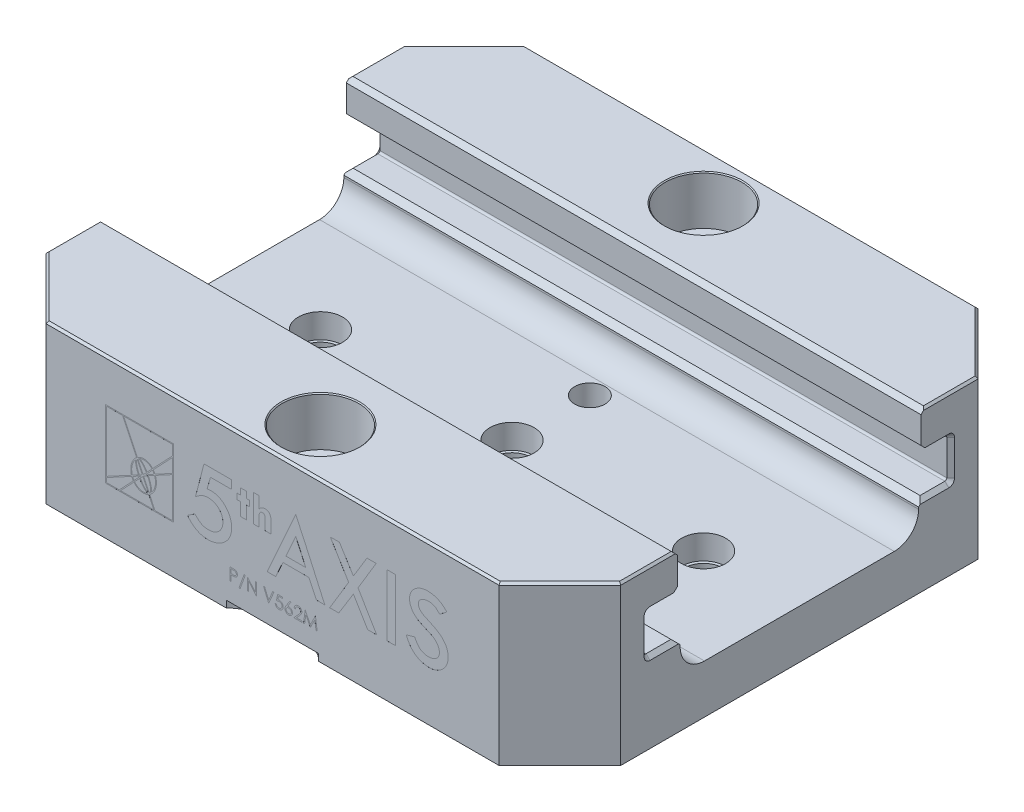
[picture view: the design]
SolidWorks part; units mm, degrees
ref_plane "Front Plane" through (0, 0, 0) normal (0, 0, 1) x (1, 0, 0)
ref_plane "Top Plane" through (0, 0, 0) normal (0, 1, 0) x (1, 0, 0)
ref_plane "Right Plane" through (0, 0, 0) normal (1, 0, 0) x (0, 0, -1)
sketch "Sketch1" plane through (0, 0, 0) normal (0, 1, 0) x (1, 0, 0)
  line L1 (-75, -62.5) -> (75, -62.5)
  line L2 (-75, -62.5) -> (-75, 62.5)
  line L3 (-75, 62.5) -> (75, 62.5)
  line L4 (75, -62.5) -> (75, 62.5)
  line L5 (-75, -62.5) -> (75, 62.5) construction
  line L6 (-75, 62.5) -> (75, -62.5) construction
  circle A0 centre (0, 0) radius 88.9 construction
  circle A1 centre (0, 0) radius 63.5 construction
  point P0 (0, 0)
  dimension "D3" = 127
  dimension "D4" = 177.8
  dimension "D1" = 150
  dimension "D2" = 125
extrude "Boss-Extrude1" add sketch "Sketch1" along normal blind 41.275
sketch "Sketch4" plane through (0, 0, 0) normal (1, 0, 0) x (0, 0, -1)
  line L0 (-31.75, 41.275) -> (31.75, 41.275)
  line L1 (-62.5, 41.275) -> (62.5, 41.275) construction
  line L2 (31.115, 12.7) -> (31.115, 20.955)
  line L3 (31.115, 20.955) -> (39.497, 20.955)
  line L4 (39.497, 20.955) -> (39.497, 31.115)
  line L5 (39.497, 31.115) -> (31.75, 31.115)
  line L6 (31.75, 31.115) -> (31.75, 41.275)
  line L7 (-31.115, 12.7) -> (-31.115, 20.955)
  line L8 (-31.115, 20.955) -> (-39.497, 20.955)
  line L9 (-39.497, 20.955) -> (-39.497, 31.115)
  line L10 (-39.497, 31.115) -> (-31.75, 31.115)
  line L11 (-31.75, 31.115) -> (-31.75, 41.275)
  line L12 (-62.5, 0) -> (62.5, 0) construction
  line L14 (-31.115, 12.7) -> (31.115, 12.7)
  line L17 (0, 0) -> (0, 41.275) construction
  point P6 (0, 12.7)
  point P14 (0, 41.275)
  dimension "D1" = 78.994
  dimension "D2" = 63.5
  dimension "D3" = 10.16
  dimension "D4" = 8.255
  dimension "D5" = 12.7
  dimension "D6" = 62.23
  dimension "D7" = 8.636
extrude "Cut-Extrude2 INTERIOR CUT" cut sketch "Sketch4" against normal through all and the other way through all
hole_wizard "CBORE for M12 SHCS1" positions "Sketch11" profile "Sketch10" counterbore size "M12" standard "ANSI Metric"
sketch "Sketch11" plane through (0, 41.275, 0) normal (0, 1, 0) x (-1, 0, 0)
  line L0 (0, 50) -> (0, -50) construction
  point P0 (0, -50)
  point P1 (0, 50)
  dimension "D1" = 100
sketch "Sketch10" plane through (0, 41.275, -50) normal (1, 0, 0) x (0, 0, 1)
  line L0 (0, 0) -> (0, 41.275)
  line L1 (0, 41.275) -> (6.5, 41.275)
  line L3 (6.5, 41.275) -> (6.5, 12.762)
  line L4 (10, 12.762) -> (6.5, 12.762)
  line L5 (10, 12.762) -> (10, 0.25)
  line L6 (10, 0.25) -> (10.25, 0)
  line L7 (10.25, 0) -> (0, 0)
  line L8 (-10, 0.25) -> (-10.25, 0) construction
  line L11 (0, -6.35) -> (0, 107.95) construction
  dimension "Thru Hole Dia." = 13
  dimension "Thru Hole Depth" = 41.275
  dimension "C'Bore Dia." = 20
  dimension "C'Bore Depth" = 12.762
  dimension "Near C'Sink Dia." = 20.5
  dimension "Near C'Sink Angle" = 90
fillet "Fillet1" radius 6.35 2 edges at (0, 12.7, -31.115) (0, 12.7, 31.115)
sketch "Sketch6" plane through (0, 0, 0) normal (0, -1, 0) x (1, 0, 0)
  line L0 (-75, 0) -> (75, 0) construction
  line L1 (-75, -62.5) -> (-75, 62.5) construction
  line L2 (75, 62.5) -> (75, -62.5) construction
  circle A0 centre (0, -10.16) radius 3.175
  circle A1 centre (0, 10.16) radius 3.175
  dimension "D1" = 6.35
  dimension "D2" = 10.16
  dimension "D3" = 11.5
extrude "Cut-Extrude4 CENTER BLOCK DP" [suppressed] cut sketch "Sketch6" against normal through all
hole_wizard "CBORE for 5/16 Socket Head Cap Screw1" positions "Sketch8" profile "Sketch7" counterbore size "5/16" standard "ANSI Inch"
sketch "Sketch8" plane through (0, 0, 0) normal (0, -1, 0) x (1, 0, 0)
  line L0 (0, -20.32) -> (0, 20.32) construction
  point P0 (0, -20.32)
  point P6 (0, 20.32)
  dimension "D1" = 40.64
sketch "Sketch7" plane through (0, 0, -20.32) normal (1, 0, 0) x (0, 0, -1)
  line L0 (0, 0) -> (0, 41.275)
  line L1 (0, 41.275) -> (3.9687, 41.275)
  line L3 (3.9687, 41.275) -> (3.9688, 6.096)
  line L4 (3.9688, 6.096) -> (6.7475, 6.096)
  line L5 (6.7475, 6.096) -> (6.7475, 0)
  line L7 (6.7475, 0) -> (0, 0)
  line L11 (0, -6.35) -> (0, 107.95) construction
  dimension "Thru Hole Dia." = 7.9375
  dimension "Thru Hole Depth" = 41.275
  dimension "C'Bore Dia." = 13.495
  dimension "C'Bore Depth" = 6.096
sketch "Sketch12" plane through (0, 0, -62.5) normal (0, 0, -1) x (-1, 0, 0)
  line L0 (16.764, 11.684) -> (42.164, 11.684) construction
  line L1 (16.764, 15.748) -> (42.164, 15.748)
  line L2 (16.764, 7.62) -> (42.164, 7.62)
  line L4 (0, 0) -> (0, 41.275) construction
  line L5 (-75, 41.275) -> (75, 41.275) construction
  line L6 (-16.764, 11.684) -> (-42.164, 11.684) construction
  line L7 (-16.764, 15.748) -> (-42.164, 15.748)
  line L8 (-16.764, 7.62) -> (-42.164, 7.62)
  line L11 (-75, 0) -> (75, 0) construction
  arc A0 (16.764, 15.748) -> (16.764, 7.62) centre (16.764, 11.684) ccw
  arc A1 (42.164, 7.62) -> (42.164, 15.748) centre (42.164, 11.684) ccw
  arc A2 (-16.764, 15.748) -> (-16.764, 7.62) centre (-16.764, 11.684) cw
  arc A3 (-42.164, 7.62) -> (-42.164, 15.748) centre (-42.164, 11.684) cw
  point P2 (29.464, 11.684)
  point P16 (-29.464, 11.684)
  dimension "D1" = 8.128
  dimension "D2" = 25.4
  dimension "D3" = 12.7
  dimension "D4" = 7.62
  dimension "D5" = 14.9262
extrude "Cut-Extrude6 CHIP CHANNELS" [suppressed] cut sketch "Sketch12" against normal blind 39.37
sketch "Sketch2" [suppressed] plane through (0, 12.7, 0) normal (0, 1, 0) x (1, 0, 0)
  line L1 (20.449, 23.495) -> (38.479, 23.495) construction
  line L2 (20.449, 31.115) -> (38.479, 31.115)
  line L3 (20.449, 15.875) -> (38.479, 15.875)
  line L5 (0, -62.5) -> (0, 62.5) construction
  line L6 (-75, -62.5) -> (75, -62.5) construction
  line L7 (75, 62.5) -> (-75, 62.5) construction
  line L8 (-75, 0) -> (75, 0) construction
  line L9 (-75, -24.765) -> (-75, 24.765) construction
  line L10 (75, -24.765) -> (75, 24.765) construction
  line L11 (-75, 31.115) -> (75, 31.115) construction
  line L12 (12.829, 23.13) -> (12.829, 24.765) construction
  line L13 (46.099, 24.765) -> (46.099, 23.13) construction
  line L14 (-20.449, 23.495) -> (-38.479, 23.495) construction
  line L15 (-20.449, 31.115) -> (-38.479, 31.115)
  line L16 (-20.449, 15.875) -> (-38.479, 15.875)
  line L17 (-20.449, -23.495) -> (-38.479, -23.495) construction
  line L18 (-20.449, -31.115) -> (-38.479, -31.115)
  line L19 (-20.449, -15.875) -> (-38.479, -15.875)
  line L20 (20.449, -23.495) -> (38.479, -23.495) construction
  line L21 (20.449, -31.115) -> (38.479, -31.115)
  line L22 (20.449, -15.875) -> (38.479, -15.875)
  arc A0 (20.449, 31.115) -> (20.449, 15.875) centre (20.449, 23.495) ccw
  arc A1 (38.479, 15.875) -> (38.479, 31.115) centre (38.479, 23.495) ccw
  arc A2 (-20.449, 31.115) -> (-20.449, 15.875) centre (-20.449, 23.495) cw
  arc A3 (-38.479, 15.875) -> (-38.479, 31.115) centre (-38.479, 23.495) cw
  arc A4 (-20.449, -31.115) -> (-20.449, -15.875) centre (-20.449, -23.495) ccw
  arc A5 (-38.479, -15.875) -> (-38.479, -31.115) centre (-38.479, -23.495) ccw
  arc A6 (20.449, -31.115) -> (20.449, -15.875) centre (20.449, -23.495) cw
  arc A7 (38.479, -15.875) -> (38.479, -31.115) centre (38.479, -23.495) cw
  point P2 (29.464, 23.495)
  point P29 (-29.464, 23.495)
  point P36 (-29.464, -23.495)
  point P43 (29.464, -23.495)
  dimension "D3" = 12.7
  dimension "D2" = 40.64
  dimension "D1" = 15.24
extrude "Cut-Extrude1 CHIP CHANNEL END" [suppressed] cut sketch "Sketch2" against normal blind 5.08 and the other way through all
mirror "Mirror1" [suppressed] about plane through (0, 0, 0) normal (0, 0, 1)
chamfer "Chamfer1" distance 15.875 angle 45 4 edges at (-75, 20.6375, -62.5) (-75, 20.6375, 62.5) (75, 20.6375, -62.5) (75, 20.6375, 62.5)
sketch "Sketch13" plane through (0, 0, 0) normal (0, -1, 0) x (1, 0, 0)
  circle A0 centre (0, 0) radius 5.0064
  dimension "D1" = 10.0127
extrude "Cut-Extrude7 CENTER LOCATING BORE" cut sketch "Sketch13" against normal blind 7.62
sketch "Sketch16" plane through (0, 0, 0) normal (0, -1, 0) x (1, 0, 0)
  line L0 (0, -62.5) -> (0, 62.5) construction
  line L1 (59.125, -62.5) -> (-59.125, -62.5) construction
  line L2 (-59.125, 62.5) -> (59.125, 62.5) construction
  circle A0 centre (-50, 0) radius 5.0063
  circle A1 centre (50, 0) radius 5.0063
  dimension "D1" = 10.0127
  dimension "D3" = 50
  dimension "D2" = 50
extrude "Cut-Extrude8 CLOCKING BORE" cut sketch "Sketch16" against normal blind 7.62
sketch "Sketch32" plane through (0, 0, 0) normal (0, -1, 0) x (1, 0, 0)
  point P0 (50, 0)
  point P1 (0, 0)
  point P3 (-50, 0)
hole_wizard "1/2-20 Tapped Hole2" positions "Sketch34" profile "Sketch33" tap size "1/2-20" standard "ANSI Inch"
sketch "Sketch34" plane through (0, 12.7, 0) normal (0, 1, 0) x (1, 0, 0)
  point P0 (50, 0)
  point P2 (0, 0)
  point P4 (-50, 0)
sketch "Sketch33" plane through (50, 12.7, 0) normal (1, 0, 0) x (0, 0, 1)
  line L0 (0, 0) -> (0, 6.35)
  line L1 (0, 6.35) -> (5.7544, 6.35)
  line L2 (5.7544, 6.35) -> (5.7544, 0)
  line L5 (5.7544, 0) -> (0, 0)
  line L10 (0, 6.35) -> (-5.7544, 6.35) construction
  line L11 (0, -6.35) -> (0, 107.95) construction
  dimension "Tap Drill Dia." = 11.5087
  dimension "Tap Drill Depth" = 6.35
  dimension "Drill Angle" = 180
hole_wizard "M6x1.0 Tapped Hole1" positions "Sketch15" profile "Sketch14" tap size "M6x1.0" standard "ANSI Metric"
sketch "Sketch15" plane through (0, 5.969, 0) normal (0, -1, 0) x (1, 0, 0)
  point P0 (0, 0)
  point P4 (-50, 0)
  point P7 (50, 0)
sketch "Sketch14" plane through (0, 5.969, 0) normal (1, 0, 0) x (0, 0, -1)
  line L0 (0, 0) -> (0, 35.306)
  line L1 (0, 35.306) -> (2.5, 35.306)
  line L2 (2.5, 35.306) -> (2.5, 0)
  line L5 (2.5, 0) -> (0, 0)
  line L11 (0, -6.35) -> (0, 107.95) construction
  dimension "Thru Tap Drill Dia." = 5
  dimension "Thru Tap Drill Depth" = 35.306
chamfer "Chamfer3" distance 1.397 angle 45 2 edges at (0, 20.955, 31.115) (0, 20.955, -31.115)
fillet "Fillet3" radius 0.508 4 edges at (0, 20.955, -39.497) (0, 31.115, -39.497) (0, 20.955, 39.497) (0, 31.115, 39.497)
chamfer "Chamfer4" distance 0.5334 angle 45 12 edges at (75, 41.275, 39.1875) (67.0625, 41.275, 54.5625) (0, 41.275, 62.5) (-67.0625, 41.275, 54.5625) (-75, 41.275, 39.1875) (75, 41.275, -39.1875) (67.0625, 41.275, -54.5625) (0, 41.275, -62.5) (-67.0625, 41.275, -54.5625) (-75, 41.275, -39.1875) (0, 41.275, 31.75) (0, 41.275, -31.75)
sketch "Sketch20" plane through (0, 0, 0) normal (0, -1, 0) x (1, 0, 0)
  line L0 (-75, 0) -> (75, 0) construction
  line L1 (-75, -46.625) -> (-75, 46.625) construction
  line L2 (75, 46.625) -> (75, -46.625) construction
  line L3 (-6.35, 67.58) -> (6.35, 67.58) construction
  line L4 (-6.35, 75.2) -> (6.35, 75.2)
  line L5 (-6.35, 59.96) -> (6.35, 59.96)
  line L6 (-59.125, 62.5) -> (59.125, 62.5) construction
  line L7 (-6.35, -67.58) -> (6.35, -67.58) construction
  line L8 (-6.35, -75.2) -> (6.35, -75.2)
  line L9 (-6.35, -59.96) -> (6.35, -59.96)
  arc A0 (-6.35, 75.2) -> (-6.35, 59.96) centre (-6.35, 67.58) ccw
  arc A1 (6.35, 59.96) -> (6.35, 75.2) centre (6.35, 67.58) ccw
  arc A2 (-6.35, -75.2) -> (-6.35, -59.96) centre (-6.35, -67.58) cw
  arc A3 (6.35, -59.96) -> (6.35, -75.2) centre (6.35, -67.58) cw
  point P8 (0, 67.58)
  point P18 (0, -67.58)
  dimension "D3" = 7.62
  dimension "D1" = 2.54
  dimension "D2" = 12.7
extrude "Cut-Extrude9 PRY SLOTS" cut sketch "Sketch20" against normal blind 1.778
sketch "Sketch26" plane through (0, 0, 0) normal (0, -1, 0) x (1, 0, 0)
  line L8 (-75, 46.625) -> (-75, -46.625)
  line L9 (-75, -46.625) -> (-59.125, -62.5)
  line L10 (-59.125, -62.5) -> (-12.0296, -62.5)
  line L11 (59.125, -62.5) -> (75, -46.625)
  line L12 (75, -46.625) -> (75, 46.625)
  line L13 (75, 46.625) -> (59.125, 62.5)
  line L14 (59.125, 62.5) -> (12.0296, 62.5)
  line L15 (-59.125, 62.5) -> (-75, 46.625)
  line L16 (-75, 46.625) -> (-75, -46.625)
  line L17 (-75, -46.625) -> (-59.125, -62.5)
  line L18 (-59.125, -62.5) -> (-12.0296, -62.5)
  line L19 (59.125, -62.5) -> (75, -46.625)
  line L20 (75, -46.625) -> (75, 46.625)
  line L21 (75, 46.625) -> (59.125, 62.5)
  line L22 (59.125, 62.5) -> (12.0296, 62.5)
  line L23 (-59.125, 62.5) -> (-75, 46.625)
  line L28 (-6.35, -59.96) -> (6.35, -59.96)
  line L29 (-6.35, -59.96) -> (6.35, -59.96)
  line L30 (12.0296, -62.5) -> (59.125, -62.5)
  line L31 (12.0296, -62.5) -> (59.125, -62.5)
  line L32 (6.35, 59.96) -> (-6.35, 59.96)
  line L33 (6.35, 59.96) -> (-6.35, 59.96)
  line L34 (-12.0296, 62.5) -> (-59.125, 62.5)
  line L35 (-12.0296, 62.5) -> (-59.125, 62.5)
  circle A0 centre (0, -50) radius 6.5 construction
  circle A1 centre (0, 50) radius 6.5 construction
  circle A2 centre (0, 50) radius 6.5
  circle A3 centre (0, -50) radius 6.5
  arc A8 (-6.35, -59.96) -> (-12.0296, -62.5) centre (-6.35, -67.58) ccw
  arc A9 (-6.35, -59.96) -> (-12.0296, -62.5) centre (-6.35, -67.58) ccw
  arc A10 (12.0296, -62.5) -> (6.35, -59.96) centre (6.35, -67.58) ccw
  arc A11 (12.0296, -62.5) -> (6.35, -59.96) centre (6.35, -67.58) ccw
  arc A12 (6.35, 59.96) -> (12.0296, 62.5) centre (6.35, 67.58) ccw
  arc A13 (6.35, 59.96) -> (12.0296, 62.5) centre (6.35, 67.58) ccw
  arc A14 (-12.0296, 62.5) -> (-6.35, 59.96) centre (-6.35, 67.58) ccw
  arc A15 (-12.0296, 62.5) -> (-6.35, 59.96) centre (-6.35, 67.58) ccw
  dimension "D1" = 0
extrude "Boss-Extrude5 MILL OP2 " [suppressed] add sketch "Sketch26" along normal blind 1.016
sketch "Sketch23" [suppressed] plane through (0, 0, 0) normal (0, -1, 0) x (1, 0, 0)
  line L8 (-75, 46.625) -> (-75, -46.625)
  line L9 (-75, -46.625) -> (-59.125, -62.5)
  line L10 (-59.125, -62.5) -> (-12.0296, -62.5)
  line L11 (59.125, -62.5) -> (75, -46.625)
  line L12 (75, -46.625) -> (75, 46.625)
  line L13 (75, 46.625) -> (59.125, 62.5)
  line L14 (59.125, 62.5) -> (12.0296, 62.5)
  line L15 (-59.125, 62.5) -> (-75, 46.625)
  line L16 (-75, 46.625) -> (-75, -46.625)
  line L17 (-75, -46.625) -> (-59.125, -62.5)
  line L18 (-59.125, -62.5) -> (-12.0296, -62.5)
  line L19 (59.125, -62.5) -> (75, -46.625)
  line L20 (75, -46.625) -> (75, 46.625)
  line L21 (75, 46.625) -> (59.125, 62.5)
  line L22 (59.125, 62.5) -> (12.0296, 62.5)
  line L23 (-59.125, 62.5) -> (-75, 46.625)
  line L28 (-6.35, -59.96) -> (6.35, -59.96)
  line L29 (-6.35, -59.96) -> (6.35, -59.96)
  line L30 (12.0296, -62.5) -> (59.125, -62.5)
  line L31 (12.0296, -62.5) -> (59.125, -62.5)
  line L32 (6.35, 59.96) -> (-6.35, 59.96)
  line L33 (6.35, 59.96) -> (-6.35, 59.96)
  line L34 (-12.0296, 62.5) -> (-59.125, 62.5)
  line L35 (-12.0296, 62.5) -> (-59.125, 62.5)
  circle A0 centre (-50, 0) radius 5.0063 construction
  circle A1 centre (0, 50) radius 6.5 construction
  circle A2 centre (0, 20.32) radius 6.7475 construction
  circle A3 centre (0, 0) radius 5.0064 construction
  circle A4 centre (0, -20.32) radius 6.7475 construction
  circle A5 centre (0, -50) radius 6.5 construction
  circle A6 centre (-50, 0) radius 5.0063
  circle A7 centre (0, 50) radius 6.5
  circle A8 centre (0, 20.32) radius 6.7475
  circle A9 centre (0, 0) radius 5.0064
  circle A10 centre (0, -20.32) radius 6.7475
  circle A11 centre (0, -50) radius 6.5
  circle A12 centre (50, 0) radius 5.0063
  arc A16 (-6.35, -59.96) -> (-12.0296, -62.5) centre (-6.35, -67.58) ccw
  arc A17 (-6.35, -59.96) -> (-12.0296, -62.5) centre (-6.35, -67.58) ccw
  arc A18 (12.0296, -62.5) -> (6.35, -59.96) centre (6.35, -67.58) ccw
  arc A19 (12.0296, -62.5) -> (6.35, -59.96) centre (6.35, -67.58) ccw
  arc A20 (6.35, 59.96) -> (12.0296, 62.5) centre (6.35, 67.58) ccw
  arc A21 (6.35, 59.96) -> (12.0296, 62.5) centre (6.35, 67.58) ccw
  arc A22 (-12.0296, 62.5) -> (-6.35, 59.96) centre (-6.35, 67.58) ccw
  arc A23 (-12.0296, 62.5) -> (-6.35, 59.96) centre (-6.35, 67.58) ccw
  dimension "D1" = 0
extrude "Boss-Extrude4 MILL OP3" [suppressed] add sketch "Sketch23" along normal blind 0.254
sketch "Sketch27" [suppressed] plane through (0, 0, 0) normal (1, 0, 0) x (0, 0, -1)
  line L0 (63.5, -1.016) -> (-63.5, -1.016)
  line L1 (46.99, -1.016) -> (-46.99, -1.016) construction
  line L2 (-63.5, -1.016) -> (-63.5, -3.048)
  line L3 (-63.5, -3.048) -> (-12.7, -3.048)
  line L4 (-12.7, -3.048) -> (-16.256, -6.604)
  line L5 (-16.256, -6.604) -> (-16.256, -6.858)
  line L6 (-16.256, -6.858) -> (16.256, -6.858)
  line L7 (0, -6.858) -> (0, -1.016) construction
  line L8 (16.256, -6.604) -> (16.256, -6.858)
  line L9 (12.7, -3.048) -> (16.256, -6.604)
  line L10 (63.5, -3.048) -> (12.7, -3.048)
  line L11 (63.5, -1.016) -> (63.5, -3.048)
  dimension "D1" = 45
  dimension "D2" = 0.254
  dimension "D3" = 25.4
  dimension "D4" = 3.81
  dimension "D5" = 127
  dimension "D6" = 3.048
extrude "Boss-Extrude6 MILL OP2 DOVETAIL" [suppressed] add sketch "Sketch27" along normal mid plane 154.94
hole_wizard "Ø7.7 (7.7) Diameter Hole1" positions "Sketch25" profile "Sketch24" hole size "Ø7.7" standard "ANSI Metric"
sketch "Sketch25" plane through (0, 12.7, 0) normal (0, 1, 0) x (-1, 0, 0)
  point P0 (0, -20.32)
  point P3 (0, 20.32)
sketch "Sketch24" plane through (0, 12.7, -20.32) normal (1, 0, 0) x (0, 0, 1)
  line L0 (0, 0) -> (0, 11.1945)
  line L1 (0, 11.1945) -> (3.8354, 8.89)
  line L2 (3.8354, 8.89) -> (3.8354, 0)
  line L5 (3.8354, 0) -> (0, 0)
  line L10 (0, 11.1945) -> (-3.8354, 8.89) construction
  line L11 (0, -6.35) -> (0, 107.95) construction
  dimension "Hole Dia." = 7.6225
  dimension "Hole Depth" = 8.89
  dimension "Drill Angle" = 118
chamfer "Chamfer5" distance 2.032 angle 45 2 edges at (0, 31.115, -31.75) (0, 31.115, 31.75)
chamfer "Chamfer6" distance 1.1684 angle 45 2 edges at (0, 41.275, -31.75) (0, 41.275, 31.75)
sketch "Sketch28" plane through (0, 41.275, 0) normal (0, 1, 0) x (1, 0, 0)
  line L6 (-74.4666, 46.4041) -> (-74.4666, 32.9184)
  line L7 (-74.4666, 32.9184) -> (74.4666, 32.9184)
  line L8 (74.4666, 32.9184) -> (74.4666, 46.4041)
  line L9 (74.4666, 46.4041) -> (58.9041, 61.9666)
  line L10 (58.9041, 61.9666) -> (-58.9041, 61.9666)
  line L11 (-58.9041, 61.9666) -> (-74.4666, 46.4041)
  line L12 (-74.4666, 46.4041) -> (-74.4666, 32.9184)
  line L13 (-74.4666, 32.9184) -> (74.4666, 32.9184)
  line L14 (74.4666, 32.9184) -> (74.4666, 46.4041)
  line L15 (74.4666, 46.4041) -> (58.9041, 61.9666)
  line L16 (58.9041, 61.9666) -> (-58.9041, 61.9666)
  line L17 (-58.9041, 61.9666) -> (-74.4666, 46.4041)
  line L18 (74.4666, -46.4041) -> (74.4666, -32.9184)
  line L19 (74.4666, -32.9184) -> (-74.4666, -32.9184)
  line L20 (-74.4666, -32.9184) -> (-74.4666, -46.4041)
  line L21 (-74.4666, -46.4041) -> (-58.9041, -61.9666)
  line L22 (-58.9041, -61.9666) -> (58.9041, -61.9666)
  line L23 (58.9041, -61.9666) -> (74.4666, -46.4041)
  line L24 (74.4666, -46.4041) -> (74.4666, -32.9184)
  line L25 (74.4666, -32.9184) -> (-74.4666, -32.9184)
  line L26 (-74.4666, -32.9184) -> (-74.4666, -46.4041)
  line L27 (-74.4666, -46.4041) -> (-58.9041, -61.9666)
  line L28 (-58.9041, -61.9666) -> (58.9041, -61.9666)
  line L29 (58.9041, -61.9666) -> (74.4666, -46.4041)
  circle A0 centre (0, -50) radius 10.25 construction
  circle A1 centre (0, -50) radius 10.25
  circle A2 centre (0, 50) radius 10.25 construction
  circle A3 centre (0, 50) radius 10.25
  dimension "D1" = 0
  dimension "D2" = 0
extrude "Boss-Extrude2 TOP SURFACE MILL OP2 AND 3 1" [suppressed] add sketch "Sketch28" along normal blind 0.2286 draft 45
chamfer "Chamfer7" distance 1.016 angle 45 20 edges at (75, 20.955, -35.7505) (75, 31.115, -36.3855) (75, 21.1038, -39.3482) (75, 30.9662, -39.3482) (75, 26.035, -39.497) (-75, 20.955, -35.7505) (-75, 31.115, -36.3855) (-75, 21.1038, -39.3482) (-75, 30.9662, -39.3482) (-75, 26.035, -39.497) (-75, 31.115, 36.3855) (-75, 20.955, 35.7505) (-75, 30.9662, 39.3482) (-75, 21.1038, 39.3482) (-75, 26.035, 39.497) (75, 31.115, 36.3855) (75, 20.955, 35.7505) (75, 30.9662, 39.3482) (75, 21.1038, 39.3482) (75, 26.035, 39.497)
ref_plane "Plane1" [suppressed] through (0, 20.6375, 0) normal (0, 1, 0) x (1, 0, 0)
sketch "Sketch29" plane through (75, 0, 0) normal (1, 0, 0) x (0, 0, -1)
  line L0 (0, 0) -> (0, 1.6452)
  line L1 (-46.625, 0) -> (46.625, 0) construction
  line L2 (0, 1.6452) -> (0, 0)
  line L3 (0, -1.358) -> (0, 0)
  circle A0 centre (0, 0) radius 0.9256
ref_plane "Plane2" through (75, 40.1066, 31.75) normal (0, -1, 0) x (-1, 0, 0)
sketch "Sketch37" plane through (0, 0, -62.5) normal (0, 0, -1) x (-1, 0, 0)
  line L78 (31.5818, 30.329) -> (29.4648, 30.329)
  line L79 (31.5818, 14.2731) -> (31.5818, 30.329)
  line L80 (29.4315, 30.2317) -> (29.4315, 14.2731)
  line L81 (26.5655, 30.329) -> (24.1555, 30.329)
  line L82 (24.3187, 14.2396) -> (26.6959, 14.2396)
  line L83 (9.0103, 18.3759) -> (10.9316, 14.2731)
  line L84 (2.2364, 18.3759) -> (9.0103, 18.3759)
  line L85 (3.0182, 20.2002) -> (8.1643, 20.2002)
  line L86 (-3.9993, 23.2302) -> (-3.9993, 26.0708)
  line L87 (-5.5171, 23.2302) -> (-3.9993, 23.2302)
  line L88 (-5.5171, 30.3625) -> (-5.5171, 23.2302)
  line L89 (-3.9993, 30.3625) -> (-5.5171, 30.3625)
  line L90 (-3.9993, 27.2737) -> (-3.9993, 30.3625)
  line L91 (-0.8833, 23.2302) -> (-0.8833, 25.9583)
  line L92 (-2.4011, 23.2302) -> (-0.8833, 23.2302)
  line L93 (-2.4011, 26.2774) -> (-2.4011, 23.2302)
  line L94 (-7.3448, 26.5811) -> (-6.4844, 26.5811)
  line L95 (-7.3448, 23.2302) -> (-7.3448, 26.5811)
  line L96 (-8.8626, 23.2302) -> (-7.3448, 23.2302)
  line L97 (-8.8626, 26.5811) -> (-8.8626, 23.2302)
  line L98 (-9.723, 26.5811) -> (-8.8626, 26.5811)
  line L99 (-9.723, 28.0643) -> (-9.723, 26.5811)
  line L100 (-8.8626, 28.0643) -> (-9.723, 28.0643)
  line L101 (-8.8626, 29.7121) -> (-8.8626, 28.0643)
  line L102 (-7.3448, 29.7121) -> (-8.8626, 29.7121)
  line L103 (-7.3448, 28.0643) -> (-7.3448, 29.7121)
  line L104 (-6.4844, 28.0643) -> (-7.3448, 28.0643)
  line L105 (-6.4844, 26.5811) -> (-6.4844, 28.0643)
  line L106 (-26.3243, 30.9152) -> (-44.0736, 30.9152)
  line L107 (-26.3243, 13.166) -> (-26.3243, 30.9152)
  line L108 (-44.0736, 13.166) -> (-26.3243, 13.166)
  line L109 (-44.0736, 30.9152) -> (-44.0736, 13.166)
  line L110 (-36.6713, 17.0962) -> (-40.1689, 13.4149)
  line L111 (-40.1689, 13.4149) -> (-31.4507, 13.4149)
  line L112 (-31.4507, 13.4149) -> (-32.7806, 16.2246)
  line L113 (-39.6164, 30.6663) -> (-43.8247, 30.6663)
  line L114 (-43.8247, 30.6663) -> (-43.8247, 14.8252)
  line L115 (-43.8247, 14.8252) -> (-37.3034, 18.3357)
  line L116 (-37.0835, 18.4541) -> (-35.5011, 19.306)
  line L117 (-35.6596, 22.8889) -> (-34.2801, 19.9744)
  line L118 (-34.2801, 19.9744) -> (-33.4239, 20.8756)
  line L119 (-37.2217, 18.097) -> (-43.8247, 14.5425)
  line L120 (-43.8247, 14.5425) -> (-43.8247, 13.4149)
  line L121 (-43.8247, 13.4149) -> (-40.5123, 13.4149)
  line L122 (-40.5123, 13.4149) -> (-36.8187, 17.3025)
  line L123 (-36.6428, 17.4876) -> (-35.3027, 18.8981)
  line L124 (-35.3942, 19.0808) -> (-37.0037, 18.2144)
  line L125 (-26.5733, 23.8295) -> (-31.0756, 21.4057)
  line L126 (-32.5661, 16.3533) -> (-31.1753, 13.4149)
  line L127 (-31.1753, 13.4149) -> (-26.5733, 13.4149)
  line L128 (-26.5733, 13.4149) -> (-26.5733, 23.8295)
  line L129 (-26.5733, 30.6663) -> (-39.341, 30.6663)
  line L130 (-31.7859, 22.5996) -> (-26.5733, 28.086)
  line L131 (-26.5733, 28.086) -> (-26.5733, 30.6663)
  line L132 (-26.5733, 24.1122) -> (-26.5733, 27.7246)
  line L133 (-26.5733, 27.7246) -> (-31.626, 22.4065)
  line L134 (-31.1705, 21.6373) -> (-26.5733, 24.1122)
  line L135 (-33.245, 21.0639) -> (-31.9582, 22.4182)
  line L136 (-35.2815, 19.4242) -> (-34.4954, 19.8474)
  line L137 (-34.4954, 19.8474) -> (-35.8493, 22.7078)
  line L138 (-35.1799, 18.666) -> (-36.4975, 17.2792)
  line L139 (-35.1207, 19.0896) -> (-34.8515, 19.373)
  line L140 (-34.8515, 19.373) -> (-35.1749, 19.1989)
  line L141 (-32.9527, 16.5882) -> (-34.3498, 19.5397)
  line L142 (-34.3498, 19.5397) -> (-34.9995, 18.8558)
  line L143 (-34.1693, 19.7403) -> (-32.681, 16.5961)
  line L144 (-33.1224, 20.3038) -> (-34.1693, 19.7403)
  line L145 (-33.2978, 20.6469) -> (-33.5989, 20.33)
  line L146 (-33.5989, 20.33) -> (-33.2343, 20.5263)
  line L147 (-33.0151, 20.6443) -> (-31.3878, 21.5203)
  line L148 (-31.7998, 22.2236) -> (-33.1174, 20.8367)
  line L149 (-31.2936, 21.2884) -> (-32.9031, 20.4219)
  line L150 (-11.1498, 30.3625) -> (-18.3478, 30.3625)
  line L151 (-11.1498, 28.1793) -> (-11.1498, 30.3625)
  line L152 (-16.6869, 28.1793) -> (-11.1498, 28.1793)
  line L153 (-39.341, 30.6663) -> (-35.7706, 23.1234)
  line L154 (-35.9755, 22.9744) -> (-39.6164, 30.6663)
  ellipse E12 centre (-34.1486, 19.7514) end of major axis (-33.8382, 23.4014) minor radius 3.1023 (-37.0835, 18.4541) -> (-36.2067, 22.4233) cw
  ellipse E13 centre (-34.1486, 19.7514) end of major axis (-35.6596, 22.8889) minor radius 1.1644 (-35.6596, 22.8889) -> (-33.4239, 20.8756) cw
  ellipse E14 centre (-34.1486, 19.7514) end of major axis (-33.8382, 23.4014) minor radius 3.1023 (-36.6428, 17.4876) -> (-37.0037, 18.2144) cw
  ellipse E15 centre (-34.1486, 19.7514) end of major axis (-35.6596, 22.8889) minor radius 1.1644 (-35.2815, 19.4242) -> (-35.8493, 22.7078) cw
  ellipse E16 centre (-34.1486, 19.7514) end of major axis (-33.8382, 23.4014) minor radius 3.1023 (-33.0648, 16.3592) -> (-36.4975, 17.2792) cw
  ellipse E17 centre (-34.1486, 19.7514) end of major axis (-35.6596, 22.8889) minor radius 1.1644 (-35.1207, 19.0896) -> (-35.1749, 19.1989) cw
  ellipse E18 centre (-34.1486, 19.7514) end of major axis (-35.6596, 22.8889) minor radius 1.1644 (-32.9527, 16.5882) -> (-34.9995, 18.8558) cw
  ellipse E19 centre (-34.1486, 19.7514) end of major axis (-35.6596, 22.8889) minor radius 1.1644 (-33.1224, 20.3038) -> (-32.681, 16.5961) cw
  ellipse E20 centre (-34.1486, 19.7514) end of major axis (-35.6596, 22.8889) minor radius 1.1644 (-33.2978, 20.6469) -> (-33.2343, 20.5263) cw
  ellipse E21 centre (-34.1486, 19.7514) end of major axis (-33.8382, 23.4014) minor radius 3.1023 (-31.7998, 22.2236) -> (-31.3878, 21.5203) cw
  ellipse E22 centre (-34.1486, 19.7514) end of major axis (-33.8382, 23.4014) minor radius 3.1023 (-31.2936, 21.2884) -> (-32.0906, 17.0795) cw
  ellipse E23 centre (-34.1486, 19.7514) end of major axis (-33.8382, 23.4014) minor radius 3.1023 (-35.2325, 23.1436) -> (-31.9582, 22.4182) cw
  spline S66 degree 3 poles (41.5797, 28.3758) (42.307, 28.091) (42.6361, 27.5026) (43.1754, 27.1378) knots 0 0 0 0 1 1 1 1
  spline S67 degree 3 poles (37.6711, 27.3004) (38.1086, 28.3917) (40.1449, 28.9369) (41.5797, 28.3758) knots 1 1 1 1 2 2 2 2
  spline S68 degree 3 poles (37.7039, 25.9974) (37.4988, 26.4504) (37.5141, 26.9082) (37.6711, 27.3004) knots 2 2 2 2 3 3 3 3
  spline S69 degree 3 poles (40.6675, 24.0115) (39.5316, 24.5206) (38.1385, 25.0374) (37.7039, 25.9974) knots 3 3 3 3 4 4 4 4
  spline S70 degree 3 poles (45.3252, 18.7995) (45.161, 21.6844) (42.868, 23.0236) (40.6675, 24.0115) knots 4 4 4 4 5 5 5 5
  spline S71 degree 3 poles (41.5143, 13.8168) (43.6378, 14.2927) (45.4735, 16.1925) (45.3252, 18.7995) knots 5 5 5 5 6 6 6 6
  spline S72 degree 3 poles (38.1279, 14.1098) (39.1123, 13.7555) (40.3981, 13.5669) (41.5143, 13.8168) knots 6 6 6 6 7 7 7 7
  spline S73 degree 3 poles (34.4141, 18.1158) (35.1146, 16.2436) (36.251, 14.7846) (38.1279, 14.1098) knots 7 7 7 7 8 8 8 8
  spline S74 degree 3 poles (36.5968, 18.7338) (35.8606, 18.5378) (35.1257, 18.3393) (34.4141, 18.1158) knots 8 8 8 8 9 9 9 9
  spline S75 degree 3 poles (38.5837, 16.3896) (37.5328, 16.9168) (37.0678, 17.8106) (36.5968, 18.7338) knots 9 9 9 9 10 10 10 10
  spline S76 degree 3 poles (42.8508, 17.4966) (42.1986, 16.079) (40.0032, 15.6791) (38.5837, 16.3896) knots 10 10 10 10 11 11 11 11
  spline S77 degree 3 poles (41.8725, 20.7864) (42.6847, 20.111) (43.4348, 18.7682) (42.8508, 17.4966) knots 11 11 11 11 12 12 12 12
  spline S78 degree 3 poles (37.8671, 22.7735) (39.1108, 22.0961) (40.8327, 21.6534) (41.8725, 20.7864) knots 12 12 12 12 13 13 13 13
  spline S79 degree 3 poles (35.2943, 27.1703) (35.0655, 25.0419) (36.3973, 23.5733) (37.8671, 22.7735) knots 13 13 13 13 14 14 14 14
  spline S80 degree 3 poles (36.8248, 29.776) (36.0504, 29.1674) (35.4205, 28.3563) (35.2943, 27.1703) knots 14 14 14 14 15 15 15 15
  spline S81 degree 3 poles (39.9833, 30.8179) (38.5841, 30.8131) (37.5506, 30.3456) (36.8248, 29.776) knots 15 15 15 15 16 16 16 16
  spline S82 degree 3 poles (44.5114, 29.0268) (43.4601, 30.1115) (41.8111, 30.8238) (39.9833, 30.8179) knots 16 16 16 16 17 17 17 17
  spline S83 degree 3 poles (44.9337, 28.5708) (44.9347, 28.607) (44.5975, 28.9362) (44.5114, 29.0268) knots 17 17 17 17 18 18 18 18
  spline S84 degree 3 poles (44.0552, 27.8539) (44.1772, 27.9514) (44.9322, 28.4309) (44.9337, 28.5708) knots 18 18 18 18 19 19 19 19
  spline S85 degree 3 poles (43.1754, 27.1378) (43.4858, 27.3524) (43.7113, 27.5804) (44.0552, 27.8539) knots 19 19 19 19 20 20 20 20
  spline S86 degree 3 poles (29.4315, 14.2731) (30.0818, 14.2096) (30.9275, 14.2307) (31.5818, 14.2731) knots 2 2 2 2 3 3 3 3
  spline S87 degree 3 poles (29.4648, 30.329) (29.4259, 30.323) (29.4291, 30.2778) (29.4315, 30.2317) knots 4 4 4 4 5 5 5 5
  spline S88 degree 3 poles (20.6056, 24.4995) (19.3364, 26.3901) (18.2278, 28.4399) (16.9571, 30.329) knots 1 1 1 1 2 2 2 2
  spline S89 degree 3 poles (24.1555, 30.329) (22.9537, 28.4045) (21.8011, 26.4293) (20.6056, 24.4995) knots 2 2 2 2 3 3 3 3
  spline S90 degree 3 poles (21.8103, 22.448) (23.3938, 25.0756) (25.0068, 27.6763) (26.5655, 30.329) knots 4 4 4 4 5 5 5 5
  spline S91 degree 3 poles (26.6959, 14.2396) (25.1137, 17.023) (23.4263, 19.7001) (21.8103, 22.448) knots 5 5 5 5 6 6 6 6
  spline S92 degree 3 poles (20.6056, 20.4282) (21.8332, 18.3549) (23.0702, 16.2921) (24.3187, 14.2396) knots 7 7 7 7 8 8 8 8
  spline S93 degree 3 poles (16.7947, 14.2396) (18.127, 16.2417) (19.308, 18.3934) (20.6056, 20.4282) knots 8 8 8 8 9 9 9 9
  spline S94 degree 3 poles (14.4164, 14.2396) (14.9916, 14.2489) (16.0152, 14.2337) (16.7947, 14.2396) knots 9 9 9 9 10 10 10 10
  spline S95 degree 3 poles (19.3682, 22.448) (17.7248, 19.7038) (16.0434, 16.9996) (14.4164, 14.2396) knots 10 10 10 10 11 11 11 11
  spline S96 degree 3 poles (14.5805, 30.2966) (16.2031, 27.7072) (17.7761, 25.0688) (19.3682, 22.448) knots 11 11 11 11 12 12 12 12
  spline S97 degree 3 poles (16.9571, 30.329) (16.1758, 30.308) (15.3073, 30.3721) (14.5805, 30.2966) knots 0 0 0 0 1 1 1 1
  spline S98 degree 3 poles (10.9316, 14.2731) (11.6073, 14.1981) (12.4185, 14.261) (13.1468, 14.2396) knots 1 1 1 1 2 2 2 2
  spline S99 degree 3 poles (0.3467, 14.2396) (0.9779, 15.6167) (1.5498, 17.0542) (2.2364, 18.3759) knots 5 5 5 5 6 6 6 6
  spline S100 degree 3 poles (-1.8997, 14.2731) (-1.3295, 14.2038) (-0.3815, 14.2563) (0.3467, 14.2396) knots 6 6 6 6 7 7 7 7
  spline S101 degree 3 poles (5.5575, 30.9152) (3.1035, 25.3364) (0.5504, 19.8557) (-1.8997, 14.2731) knots 7 7 7 7 8 8 8 8
  spline S102 degree 3 poles (13.1468, 14.2396) (10.6546, 19.8352) (8.1396, 25.4087) (5.5575, 30.9152) knots 0 0 0 0 1 1 1 1
  spline S103 degree 3 poles (5.5575, 25.9) (4.7259, 23.985) (3.8527, 22.1111) (3.0182, 20.2002) knots 2 2 2 2 3 3 3 3
  spline S104 degree 3 poles (8.1643, 20.2002) (7.3138, 22.1196) (6.4807, 24.054) (5.5575, 25.9) knots 1 1 1 1 2 2 2 2
  spline S105 degree 3 poles (-0.8833, 25.9583) (-0.856, 26.398) (-0.9231, 27.1395) (-1.6468, 28.2407) (-3.0429, 28.2501) (-3.8375, 27.6325) (-3.9993, 27.2737) knots 0.003707 0.003707 0.003707 0.003707 0.272214 0.451698 0.751293 1 1 1 1
  spline S106 degree 3 poles (-3.9993, 26.0708) (-3.9859, 26.1946) (-3.9218, 26.4502) (-3.6718, 26.8208) (-3.1845, 27.02) (-2.6459, 26.8706) (-2.4632, 26.5205) (-2.4125, 26.3311) (-2.4011, 26.2774) knots 0.032272 0.032272 0.032272 0.032272 0.137844 0.245999 0.399968 0.550551 0.668357 0.714576 0.714576 0.714576 0.714576
  spline S107 degree 3 poles (-32.7806, 16.2246) (-32.9047, 16.1565) (-33.4472, 15.9032) (-34.4891, 15.7487) (-35.7465, 16.1611) (-36.4115, 16.7587) (-36.6713, 17.0962) knots 2.395898 2.395898 2.395898 2.395898 2.516665 2.909364 3.302063 3.655059 3.655059 3.655059 3.655059
  spline S108 degree 3 poles (-37.3034, 18.3357) (-37.471, 18.8762) (-37.652, 20.4855) (-36.8988, 22.1662) (-36.0852, 22.8882) (-35.9755, 22.9744) knots 0.668663 0.668663 0.668663 0.668663 1.116582 1.90198 2.018716 2.018716 2.018716 2.018716
  spline S109 degree 3 poles (-35.5011, 19.306) (-35.6701, 19.6734) (-35.986, 20.4794) (-36.2073, 21.4241) (-36.2474, 22.0577) (-36.2252, 22.3173) (-36.2067, 22.4233) knots 0.436793 0.436793 0.436793 0.436793 0.777427 1.170126 1.366475 1.518731 1.518731 1.518731 1.518731
  spline S110 degree 3 poles (-36.8187, 17.3025) (-36.9805, 17.5468) (-37.1155, 17.8144) (-37.2217, 18.097) knots 2.085522 2.085522 2.085522 2.085522 2.326167 2.326167 2.326167 2.326167
  spline S111 degree 3 poles (-35.3027, 18.8981) (-35.3337, 18.9587) (-35.3643, 19.0196) (-35.3942, 19.0808) knots 1.588658 1.588658 1.588658 1.588658 1.646034 1.646034 1.646034 1.646034
  spline S112 degree 3 poles (-31.0756, 21.4057) (-30.8485, 20.8011) (-30.608, 19.1004) (-31.4455, 17.2315) (-32.367, 16.4831) (-32.5661, 16.3533) knots 3.725913 3.725913 3.725913 3.725913 4.240639 5.026037 5.227115 5.227115 5.227115 5.227115
  spline S113 degree 3 poles (-31.626, 22.4065) (-31.5968, 22.3686) (-31.4217, 22.1314) (-31.2739, 21.8692) (-31.1705, 21.6373) knots 5.293867 5.293867 5.293867 5.293867 5.333571 5.53749 5.53749 5.53749 5.53749
  spline S114 degree 3 poles (-35.2325, 23.1436) (-35.1669, 23.125) (-34.9802, 23.0518) (-34.6713, 22.8556) (-34.173, 22.4038) (-33.683, 21.7823) (-33.3437, 21.2345) (-33.245, 21.0639) knots 4.9358 4.9358 4.9358 4.9358 5.041108 5.237458 5.433807 5.826506 5.995794 5.995794 5.995794 5.995794
  spline S115 degree 3 poles (-33.0648, 16.3592) (-33.1304, 16.3777) (-33.3171, 16.451) (-33.626, 16.6472) (-34.1243, 17.099) (-34.6622, 17.7812) (-35.0426, 18.4143) (-35.1799, 18.666) knots 1.720085 1.720085 1.720085 1.720085 1.825393 2.021742 2.218092 2.610791 2.854201 2.854201 2.854201 2.854201
  spline S116 degree 3 poles (-33.1174, 20.8367) (-33.0828, 20.7732) (-33.0486, 20.709) (-33.0151, 20.6443) knots 4.800184 4.800184 4.800184 4.800184 4.861678 4.861678 4.861678 4.861678
  spline S117 degree 3 poles (-32.9031, 20.4219) (-32.8937, 20.4028) (-32.6807, 19.9639) (-32.3236, 19.0762) (-32.09, 18.0786) (-32.0499, 17.445) (-32.0721, 17.1855) (-32.0906, 17.0795) knots 3.578386 3.578386 3.578386 3.578386 3.596247 3.988946 4.381645 4.577995 4.73025 4.73025 4.73025 4.73025
  spline S118 degree 3 poles (-17.5662, 25.118) (-17.2618, 26.1271) (-17.0019, 27.1817) (-16.6869, 28.1793) knots 3 3 3 3 4 4 4 4
  spline S119 degree 3 poles (-12.9089, 23.6845) (-13.9709, 24.7479) (-15.4783, 25.4588) (-17.5662, 25.118) knots 4 4 4 4 5 5 5 5
  spline S120 degree 3 poles (-11.1821, 19.1247) (-11.0696, 21.1722) (-11.859, 22.6353) (-12.9089, 23.6845) knots 5 5 5 5 6 6 6 6
  spline S121 degree 3 poles (-15.8401, 13.9143) (-13.4457, 14.4519) (-11.3338, 16.387) (-11.1821, 19.1247) knots 6 6 6 6 7 7 7 7
  spline S122 degree 3 poles (-22.6789, 16.5852) (-21.4425, 14.7638) (-19.0022, 13.2036) (-15.8401, 13.9143) knots 7 7 7 7 8 8 8 8
  spline S123 degree 3 poles (-20.7574, 17.8545) (-21.3566, 17.3901) (-22.0747, 17.0433) (-22.6789, 16.5852) knots 8 8 8 8 9 9 9 9
  spline S124 degree 3 poles (-17.3056, 16.0314) (-19.0111, 16.0457) (-19.8662, 16.9597) (-20.7574, 17.8545) knots 9 9 9 9 10 10 10 10
  spline S125 degree 3 poles (-13.4626, 19.8744) (-13.3317, 17.7254) (-14.8619, 16.011) (-17.3056, 16.0314) knots 10 10 10 10 11 11 11 11
  spline S126 degree 3 poles (-17.338, 23.2621) (-15.2979, 23.2811) (-13.5853, 21.9102) (-13.4626, 19.8744) knots 11 11 11 11 12 12 12 12
  spline S127 degree 3 poles (-20.3019, 22.0567) (-19.5277, 22.6829) (-18.7157, 23.2486) (-17.338, 23.2621) knots 12 12 12 12 13 13 13 13
  spline S128 degree 3 poles (-20.595, 21.8935) (-20.4672, 21.8422) (-20.3722, 22) (-20.3019, 22.0567) knots 13 13 13 13 14 14 14 14
  spline S129 degree 3 poles (-18.4129, 30.264) (-19.138, 27.4717) (-19.8465, 24.6627) (-20.595, 21.8935) knots 14 14 14 14 15 15 15 15
  spline S130 degree 3 poles (-18.3478, 30.3625) (-18.3934, 30.3532) (-18.3849, 30.2906) (-18.4129, 30.264) knots 15 15 15 15 16 16 16 16
  spline S131 degree 3 poles (-35.7706, 23.1234) (-35.5692, 23.2588) (-34.9469, 23.5852) (-34.2597, 23.6871) (-33.8171, 23.6494) (-33.3745, 23.6118) (-32.6277, 23.3669) (-32.0113, 22.8527) (-31.7859, 22.5996) knots 5.607073 5.607073 5.607073 5.607073 5.812022 6.204721 6.204721 6.204721 6.59742 6.880833 6.880833 6.880833 6.880833
extrude "Cut-Extrude1" cut sketch "Sketch37" against normal blind 0.0025
sketch "Sketch38" plane through (0, 0, 62.5) normal (0, 0, 1) x (1, 0, 0)
  line L78 (32.0789, 29.6477) -> (29.9619, 29.6477)
  line L79 (32.0789, 13.5918) -> (32.0789, 29.6477)
  line L80 (29.9286, 29.5504) -> (29.9286, 13.5918)
  line L81 (27.0626, 29.6477) -> (24.6526, 29.6477)
  line L82 (24.8158, 13.5583) -> (27.193, 13.5583)
  line L83 (9.5074, 17.6946) -> (11.4287, 13.5918)
  line L84 (2.7335, 17.6946) -> (9.5074, 17.6946)
  line L85 (3.5153, 19.5189) -> (8.6614, 19.5189)
  line L86 (-3.5022, 22.5489) -> (-3.5022, 25.3895)
  line L87 (-5.02, 22.5489) -> (-3.5022, 22.5489)
  line L88 (-5.02, 29.6812) -> (-5.02, 22.5489)
  line L89 (-3.5022, 29.6812) -> (-5.02, 29.6812)
  line L90 (-3.5022, 26.5924) -> (-3.5022, 29.6812)
  line L91 (-0.3862, 22.5489) -> (-0.3862, 25.277)
  line L92 (-1.904, 22.5489) -> (-0.3862, 22.5489)
  line L93 (-1.904, 25.5961) -> (-1.904, 22.5489)
  line L94 (-6.8477, 25.8998) -> (-5.9873, 25.8998)
  line L95 (-6.8477, 22.5489) -> (-6.8477, 25.8998)
  line L96 (-8.3655, 22.5489) -> (-6.8477, 22.5489)
  line L97 (-8.3655, 25.8998) -> (-8.3655, 22.5489)
  line L98 (-9.2259, 25.8998) -> (-8.3655, 25.8998)
  line L99 (-9.2259, 27.383) -> (-9.2259, 25.8998)
  line L100 (-8.3655, 27.383) -> (-9.2259, 27.383)
  line L101 (-8.3655, 29.0308) -> (-8.3655, 27.383)
  line L102 (-6.8477, 29.0308) -> (-8.3655, 29.0308)
  line L103 (-6.8477, 27.383) -> (-6.8477, 29.0308)
  line L104 (-5.9873, 27.383) -> (-6.8477, 27.383)
  line L105 (-5.9873, 25.8998) -> (-5.9873, 27.383)
  line L106 (-25.8272, 30.2339) -> (-43.5765, 30.2339)
  line L107 (-25.8272, 12.4847) -> (-25.8272, 30.2339)
  line L108 (-43.5765, 12.4847) -> (-25.8272, 12.4847)
  line L109 (-43.5765, 30.2339) -> (-43.5765, 12.4847)
  line L110 (-36.1742, 16.4149) -> (-39.6718, 12.7336)
  line L111 (-39.6718, 12.7336) -> (-30.9536, 12.7336)
  line L112 (-30.9536, 12.7336) -> (-32.2835, 15.5433)
  line L113 (-35.4784, 22.2931) -> (-39.1192, 29.985)
  line L114 (-39.1192, 29.985) -> (-43.3276, 29.985)
  line L115 (-43.3276, 29.985) -> (-43.3276, 14.1439)
  line L116 (-43.3276, 14.1439) -> (-36.8063, 17.6545)
  line L117 (-36.5864, 17.7728) -> (-35.004, 18.6247)
  line L118 (-35.1625, 22.2076) -> (-33.783, 19.2931)
  line L119 (-33.783, 19.2931) -> (-32.9268, 20.1943)
  line L120 (-36.7246, 17.4157) -> (-43.3276, 13.8612)
  line L121 (-43.3276, 13.8612) -> (-43.3276, 12.7336)
  line L122 (-43.3276, 12.7336) -> (-40.0152, 12.7336)
  line L123 (-40.0152, 12.7336) -> (-36.3216, 16.6212)
  line L124 (-36.1457, 16.8063) -> (-34.8056, 18.2168)
  line L125 (-34.8971, 18.3995) -> (-36.5066, 17.5331)
  line L126 (-26.0762, 23.1482) -> (-30.5785, 20.7244)
  line L127 (-32.069, 15.672) -> (-30.6782, 12.7336)
  line L128 (-30.6782, 12.7336) -> (-26.0762, 12.7336)
  line L129 (-26.0762, 12.7336) -> (-26.0762, 23.1482)
  line L130 (-26.0762, 29.985) -> (-38.8439, 29.985)
  line L131 (-38.8439, 29.985) -> (-35.2735, 22.4421)
  line L132 (-31.2888, 21.9183) -> (-26.0762, 27.4047)
  line L133 (-26.0762, 27.4047) -> (-26.0762, 29.985)
  line L134 (-26.0762, 23.4309) -> (-26.0762, 27.0433)
  line L135 (-26.0762, 27.0433) -> (-31.1289, 21.7253)
  line L136 (-30.6734, 20.956) -> (-26.0762, 23.4309)
  line L137 (-32.7479, 20.3826) -> (-31.4611, 21.7369)
  line L138 (-34.7844, 18.7429) -> (-33.9983, 19.1661)
  line L139 (-33.9983, 19.1661) -> (-35.3522, 22.0265)
  line L140 (-34.6828, 17.9847) -> (-36.0004, 16.5979)
  line L141 (-34.6236, 18.4083) -> (-34.3544, 18.6917)
  line L142 (-34.3544, 18.6917) -> (-34.6778, 18.5176)
  line L143 (-32.4556, 15.9069) -> (-33.8526, 18.8584)
  line L144 (-33.8526, 18.8584) -> (-34.5024, 18.1745)
  line L145 (-33.6722, 19.059) -> (-32.1839, 15.9148)
  line L146 (-32.6253, 19.6225) -> (-33.6722, 19.059)
  line L147 (-32.8007, 19.9657) -> (-33.1017, 19.6488)
  line L148 (-33.1017, 19.6488) -> (-32.7372, 19.845)
  line L149 (-32.518, 19.963) -> (-30.8907, 20.8391)
  line L150 (-31.3027, 21.5423) -> (-32.6203, 20.1555)
  line L151 (-30.7965, 20.6071) -> (-32.406, 19.7406)
  line L152 (-10.6526, 29.6812) -> (-17.8507, 29.6812)
  line L153 (-10.6526, 27.498) -> (-10.6526, 29.6812)
  line L154 (-16.1898, 27.498) -> (-10.6526, 27.498)
  ellipse E12 centre (-33.6515, 19.0701) end of major axis (-33.3411, 22.7201) minor radius 3.1023 (-36.5864, 17.7728) -> (-35.7096, 21.742) cw
  ellipse E13 centre (-33.6515, 19.0701) end of major axis (-35.1625, 22.2076) minor radius 1.1644 (-35.1625, 22.2076) -> (-32.9268, 20.1943) cw
  ellipse E14 centre (-33.6515, 19.0701) end of major axis (-33.3411, 22.7201) minor radius 3.1023 (-36.1457, 16.8063) -> (-36.5066, 17.5331) cw
  ellipse E15 centre (-33.6515, 19.0701) end of major axis (-33.3411, 22.7201) minor radius 3.1023 (-34.7354, 22.4623) -> (-31.4611, 21.7369) cw
  ellipse E16 centre (-33.6515, 19.0701) end of major axis (-35.1625, 22.2076) minor radius 1.1644 (-34.7844, 18.7429) -> (-35.3522, 22.0265) cw
  ellipse E17 centre (-33.6515, 19.0701) end of major axis (-33.3411, 22.7201) minor radius 3.1023 (-32.5677, 15.6779) -> (-36.0004, 16.5979) cw
  ellipse E18 centre (-33.6515, 19.0701) end of major axis (-35.1625, 22.2076) minor radius 1.1644 (-34.6236, 18.4083) -> (-34.6778, 18.5176) cw
  ellipse E19 centre (-33.6515, 19.0701) end of major axis (-35.1625, 22.2076) minor radius 1.1644 (-32.4556, 15.9069) -> (-34.5024, 18.1745) cw
  ellipse E20 centre (-33.6515, 19.0701) end of major axis (-35.1625, 22.2076) minor radius 1.1644 (-32.6253, 19.6225) -> (-32.1839, 15.9148) cw
  ellipse E21 centre (-33.6515, 19.0701) end of major axis (-35.1625, 22.2076) minor radius 1.1644 (-32.8007, 19.9657) -> (-32.7372, 19.845) cw
  ellipse E22 centre (-33.6515, 19.0701) end of major axis (-33.3411, 22.7201) minor radius 3.1023 (-31.3027, 21.5423) -> (-30.8907, 20.8391) cw
  ellipse E23 centre (-33.6515, 19.0701) end of major axis (-33.3411, 22.7201) minor radius 3.1023 (-30.7965, 20.6071) -> (-31.5935, 16.3982) cw
  spline S66 degree 3 poles (42.0768, 27.6945) (42.8041, 27.4097) (43.1332, 26.8213) (43.6725, 26.4565) knots 0 0 0 0 1 1 1 1
  spline S67 degree 3 poles (38.1682, 26.6191) (38.6057, 27.7104) (40.642, 28.2556) (42.0768, 27.6945) knots 1 1 1 1 2 2 2 2
  spline S68 degree 3 poles (38.201, 25.3161) (37.9959, 25.7691) (38.0112, 26.2269) (38.1682, 26.6191) knots 2 2 2 2 3 3 3 3
  spline S69 degree 3 poles (41.1646, 23.3302) (40.0287, 23.8393) (38.6356, 24.3561) (38.201, 25.3161) knots 3 3 3 3 4 4 4 4
  spline S70 degree 3 poles (45.8223, 18.1182) (45.6581, 21.0031) (43.3651, 22.3423) (41.1646, 23.3302) knots 4 4 4 4 5 5 5 5
  spline S71 degree 3 poles (42.0114, 13.1355) (44.1349, 13.6114) (45.9706, 15.5112) (45.8223, 18.1182) knots 5 5 5 5 6 6 6 6
  spline S72 degree 3 poles (38.625, 13.4285) (39.6094, 13.0743) (40.8952, 12.8856) (42.0114, 13.1355) knots 6 6 6 6 7 7 7 7
  spline S73 degree 3 poles (34.9112, 17.4345) (35.6117, 15.5623) (36.7481, 14.1033) (38.625, 13.4285) knots 7 7 7 7 8 8 8 8
  spline S74 degree 3 poles (37.0939, 18.0525) (36.3577, 17.8565) (35.6228, 17.658) (34.9112, 17.4345) knots 8 8 8 8 9 9 9 9
  spline S75 degree 3 poles (39.0808, 15.7083) (38.0299, 16.2355) (37.5649, 17.1293) (37.0939, 18.0525) knots 9 9 9 9 10 10 10 10
  spline S76 degree 3 poles (43.3479, 16.8153) (42.6957, 15.3977) (40.5003, 14.9978) (39.0808, 15.7083) knots 10 10 10 10 11 11 11 11
  spline S77 degree 3 poles (42.3696, 20.1051) (43.1818, 19.4297) (43.9319, 18.0869) (43.3479, 16.8153) knots 11 11 11 11 12 12 12 12
  spline S78 degree 3 poles (38.3642, 22.0922) (39.6079, 21.4148) (41.3298, 20.9721) (42.3696, 20.1051) knots 12 12 12 12 13 13 13 13
  spline S79 degree 3 poles (35.7914, 26.489) (35.5626, 24.3606) (36.8944, 22.892) (38.3642, 22.0922) knots 13 13 13 13 14 14 14 14
  spline S80 degree 3 poles (37.3219, 29.0947) (36.5476, 28.4861) (35.9176, 27.675) (35.7914, 26.489) knots 14 14 14 14 15 15 15 15
  spline S81 degree 3 poles (40.4804, 30.1366) (39.0812, 30.1318) (38.0477, 29.6643) (37.3219, 29.0947) knots 15 15 15 15 16 16 16 16
  spline S82 degree 3 poles (45.0085, 28.3456) (43.9572, 29.4303) (42.3082, 30.1425) (40.4804, 30.1366) knots 16 16 16 16 17 17 17 17
  spline S83 degree 3 poles (45.4308, 27.8895) (45.4318, 27.9257) (45.0946, 28.2549) (45.0085, 28.3456) knots 17 17 17 17 18 18 18 18
  spline S84 degree 3 poles (44.5523, 27.1726) (44.6743, 27.2701) (45.4293, 27.7496) (45.4308, 27.8895) knots 18 18 18 18 19 19 19 19
  spline S85 degree 3 poles (43.6725, 26.4565) (43.9829, 26.6711) (44.2084, 26.8991) (44.5523, 27.1726) knots 19 19 19 19 20 20 20 20
  spline S86 degree 3 poles (29.9286, 13.5918) (30.5789, 13.5283) (31.4246, 13.5494) (32.0789, 13.5918) knots 2 2 2 2 3 3 3 3
  spline S87 degree 3 poles (29.9619, 29.6477) (29.923, 29.6417) (29.9262, 29.5965) (29.9286, 29.5504) knots 4 4 4 4 5 5 5 5
  spline S88 degree 3 poles (21.1027, 23.8182) (19.8335, 25.7088) (18.7249, 27.7586) (17.4542, 29.6477) knots 1 1 1 1 2 2 2 2
  spline S89 degree 3 poles (24.6526, 29.6477) (23.4508, 27.7232) (22.2982, 25.748) (21.1027, 23.8182) knots 2 2 2 2 3 3 3 3
  spline S90 degree 3 poles (22.3074, 21.7667) (23.8909, 24.3943) (25.5039, 26.9951) (27.0626, 29.6477) knots 4 4 4 4 5 5 5 5
  spline S91 degree 3 poles (27.193, 13.5583) (25.6108, 16.3417) (23.9234, 19.0188) (22.3074, 21.7667) knots 5 5 5 5 6 6 6 6
  spline S92 degree 3 poles (21.1027, 19.7469) (22.3303, 17.6736) (23.5673, 15.6108) (24.8158, 13.5583) knots 7 7 7 7 8 8 8 8
  spline S93 degree 3 poles (17.2918, 13.5583) (18.6241, 15.5604) (19.8051, 17.7121) (21.1027, 19.7469) knots 8 8 8 8 9 9 9 9
  spline S94 degree 3 poles (14.9135, 13.5583) (15.4887, 13.5676) (16.5123, 13.5524) (17.2918, 13.5583) knots 9 9 9 9 10 10 10 10
  spline S95 degree 3 poles (19.8653, 21.7667) (18.2219, 19.0225) (16.5405, 16.3183) (14.9135, 13.5583) knots 10 10 10 10 11 11 11 11
  spline S96 degree 3 poles (15.0776, 29.6153) (16.7002, 27.0259) (18.2732, 24.3875) (19.8653, 21.7667) knots 11 11 11 11 12 12 12 12
  spline S97 degree 3 poles (17.4542, 29.6477) (16.6729, 29.6267) (15.8044, 29.6908) (15.0776, 29.6153) knots 0 0 0 0 1 1 1 1
  spline S98 degree 3 poles (11.4287, 13.5918) (12.1044, 13.5168) (12.9156, 13.5797) (13.6439, 13.5583) knots 1 1 1 1 2 2 2 2
  spline S99 degree 3 poles (0.8438, 13.5583) (1.475, 14.9354) (2.0469, 16.3729) (2.7335, 17.6946) knots 5 5 5 5 6 6 6 6
  spline S100 degree 3 poles (-1.4026, 13.5918) (-0.8324, 13.5225) (0.1156, 13.575) (0.8438, 13.5583) knots 6 6 6 6 7 7 7 7
  spline S101 degree 3 poles (6.0546, 30.2339) (3.6006, 24.6551) (1.0475, 19.1744) (-1.4026, 13.5918) knots 7 7 7 7 8 8 8 8
  spline S102 degree 3 poles (13.6439, 13.5583) (11.1517, 19.154) (8.6367, 24.7274) (6.0546, 30.2339) knots 0 0 0 0 1 1 1 1
  spline S103 degree 3 poles (6.0546, 25.2187) (5.223, 23.3037) (4.3498, 21.4298) (3.5153, 19.5189) knots 2 2 2 2 3 3 3 3
  spline S104 degree 3 poles (8.6614, 19.5189) (7.8109, 21.4383) (6.9778, 23.3727) (6.0546, 25.2187) knots 1 1 1 1 2 2 2 2
  spline S105 degree 3 poles (-0.3862, 25.277) (-0.3589, 25.7167) (-0.426, 26.4582) (-1.1497, 27.5594) (-2.5458, 27.5688) (-3.3404, 26.9512) (-3.5022, 26.5924) knots 0.003707 0.003707 0.003707 0.003707 0.272214 0.451698 0.751293 1 1 1 1
  spline S106 degree 3 poles (-3.5022, 25.3895) (-3.4888, 25.5133) (-3.4247, 25.7689) (-3.1747, 26.1395) (-2.6874, 26.3387) (-2.1488, 26.1893) (-1.9661, 25.8392) (-1.9154, 25.6499) (-1.904, 25.5961) knots 0.032272 0.032272 0.032272 0.032272 0.137844 0.245999 0.399968 0.550551 0.668357 0.714576 0.714576 0.714576 0.714576
  spline S107 degree 3 poles (-32.2835, 15.5433) (-32.4076, 15.4752) (-32.9501, 15.2219) (-33.992, 15.0675) (-35.2494, 15.4798) (-35.9144, 16.0774) (-36.1742, 16.4149) knots 2.395898 2.395898 2.395898 2.395898 2.516665 2.909364 3.302063 3.655059 3.655059 3.655059 3.655059
  spline S108 degree 3 poles (-36.8063, 17.6545) (-36.9739, 18.1949) (-37.1549, 19.8042) (-36.4017, 21.4849) (-35.5881, 22.2069) (-35.4784, 22.2931) knots 0.668663 0.668663 0.668663 0.668663 1.116582 1.90198 2.018716 2.018716 2.018716 2.018716
  spline S109 degree 3 poles (-35.004, 18.6247) (-35.173, 18.9921) (-35.4889, 19.7981) (-35.7102, 20.7428) (-35.7503, 21.3764) (-35.7281, 21.636) (-35.7096, 21.742) knots 0.436793 0.436793 0.436793 0.436793 0.777427 1.170126 1.366475 1.518731 1.518731 1.518731 1.518731
  spline S110 degree 3 poles (-36.3216, 16.6212) (-36.4834, 16.8655) (-36.6184, 17.1331) (-36.7246, 17.4157) knots 2.085522 2.085522 2.085522 2.085522 2.326167 2.326167 2.326167 2.326167
  spline S111 degree 3 poles (-34.8056, 18.2168) (-34.8366, 18.2774) (-34.8672, 18.3383) (-34.8971, 18.3995) knots 1.588658 1.588658 1.588658 1.588658 1.646034 1.646034 1.646034 1.646034
  spline S112 degree 3 poles (-30.5785, 20.7244) (-30.3514, 20.1198) (-30.1109, 18.4191) (-30.9484, 16.5502) (-31.8699, 15.8018) (-32.069, 15.672) knots 3.725913 3.725913 3.725913 3.725913 4.240639 5.026037 5.227115 5.227115 5.227115 5.227115
  spline S113 degree 3 poles (-35.2735, 22.4421) (-35.0721, 22.5775) (-34.4498, 22.9039) (-33.7626, 23.0058) (-33.32, 22.9681) (-32.8774, 22.9305) (-32.1306, 22.6856) (-31.5142, 22.1715) (-31.2888, 21.9183) knots 5.607073 5.607073 5.607073 5.607073 5.812022 6.204721 6.204721 6.204721 6.59742 6.880833 6.880833 6.880833 6.880833
  spline S114 degree 3 poles (-31.1289, 21.7253) (-31.0996, 21.6873) (-30.9246, 21.4501) (-30.7768, 21.1879) (-30.6734, 20.956) knots 5.293867 5.293867 5.293867 5.293867 5.333571 5.53749 5.53749 5.53749 5.53749
  spline S115 degree 3 poles (-34.7354, 22.4623) (-34.6698, 22.4437) (-34.4831, 22.3705) (-34.1742, 22.1743) (-33.6759, 21.7225) (-33.1859, 21.101) (-32.8466, 20.5532) (-32.7479, 20.3826) knots 4.9358 4.9358 4.9358 4.9358 5.041108 5.237458 5.433807 5.826506 5.995794 5.995794 5.995794 5.995794
  spline S116 degree 3 poles (-32.5677, 15.6779) (-32.6333, 15.6964) (-32.82, 15.7697) (-33.1289, 15.9659) (-33.6272, 16.4177) (-34.1651, 17.0999) (-34.5455, 17.733) (-34.6828, 17.9847) knots 1.720085 1.720085 1.720085 1.720085 1.825393 2.021742 2.218092 2.610791 2.854201 2.854201 2.854201 2.854201
  spline S117 degree 3 poles (-32.6203, 20.1555) (-32.5857, 20.0919) (-32.5515, 20.0277) (-32.518, 19.963) knots 4.800184 4.800184 4.800184 4.800184 4.861678 4.861678 4.861678 4.861678
  spline S118 degree 3 poles (-32.406, 19.7406) (-32.3966, 19.7216) (-32.1836, 19.2826) (-31.8265, 18.395) (-31.5929, 17.3973) (-31.5528, 16.7637) (-31.575, 16.5042) (-31.5935, 16.3982) knots 3.578386 3.578386 3.578386 3.578386 3.596247 3.988946 4.381645 4.577995 4.73025 4.73025 4.73025 4.73025
  spline S119 degree 3 poles (-17.0691, 24.4367) (-16.7647, 25.4458) (-16.5048, 26.5004) (-16.1898, 27.498) knots 3 3 3 3 4 4 4 4
  spline S120 degree 3 poles (-12.4118, 23.0032) (-13.4738, 24.0666) (-14.9812, 24.7775) (-17.0691, 24.4367) knots 4 4 4 4 5 5 5 5
  spline S121 degree 3 poles (-10.685, 18.4434) (-10.5725, 20.4909) (-11.3619, 21.954) (-12.4118, 23.0032) knots 5 5 5 5 6 6 6 6
  spline S122 degree 3 poles (-15.343, 13.233) (-12.9486, 13.7707) (-10.8367, 15.7057) (-10.685, 18.4434) knots 6 6 6 6 7 7 7 7
  spline S123 degree 3 poles (-22.1818, 15.9039) (-20.9454, 14.0825) (-18.5051, 12.5223) (-15.343, 13.233) knots 7 7 7 7 8 8 8 8
  spline S124 degree 3 poles (-20.2603, 17.1732) (-20.8595, 16.7088) (-21.5776, 16.362) (-22.1818, 15.9039) knots 8 8 8 8 9 9 9 9
  spline S125 degree 3 poles (-16.8085, 15.3501) (-18.514, 15.3644) (-19.3691, 16.2784) (-20.2603, 17.1732) knots 9 9 9 9 10 10 10 10
  spline S126 degree 3 poles (-12.9655, 19.1931) (-12.8346, 17.0442) (-14.3648, 15.3297) (-16.8085, 15.3501) knots 10 10 10 10 11 11 11 11
  spline S127 degree 3 poles (-16.8409, 22.5808) (-14.8008, 22.5998) (-13.0882, 21.2289) (-12.9655, 19.1931) knots 11 11 11 11 12 12 12 12
  spline S128 degree 3 poles (-19.8048, 21.3754) (-19.0306, 22.0016) (-18.2186, 22.5673) (-16.8409, 22.5808) knots 12 12 12 12 13 13 13 13
  spline S129 degree 3 poles (-20.0979, 21.2122) (-19.9701, 21.1609) (-19.8751, 21.3187) (-19.8048, 21.3754) knots 13 13 13 13 14 14 14 14
  spline S130 degree 3 poles (-17.9158, 29.5827) (-18.6409, 26.7904) (-19.3494, 23.9814) (-20.0979, 21.2122) knots 14 14 14 14 15 15 15 15
  spline S131 degree 3 poles (-17.8507, 29.6812) (-17.8963, 29.6719) (-17.8878, 29.6093) (-17.9158, 29.5827) knots 15 15 15 15 16 16 16 16
extrude "Cut-Extrude2" cut sketch "Sketch38" against normal blind 0.0025
sketch "Sketch39" plane through (0, 0, 62.5) normal (0, 0, 1) x (1, 0, 0)
  text T0 "P/N V562M"
extrude "Cut-Extrude3" cut sketch "Sketch39" against normal blind 0.0025
sketch "Sketch40" plane through (0, 0, -62.5) normal (0, 0, -1) x (-1, 0, 0)
  text T0 "P/N V562M"
extrude "Cut-Extrude4" cut sketch "Sketch40" against normal blind 0.0025
